VERSION 5.7 ;
  NOWIREEXTENSIONATPIN ON ;
  DIVIDERCHAR "/" ;
  BUSBITCHARS "[]" ;
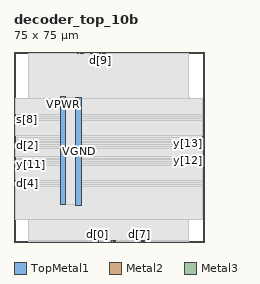
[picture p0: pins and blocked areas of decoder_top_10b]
MACRO decoder_top_10b
  CLASS BLOCK ;
  FOREIGN decoder_top_10b ;
  ORIGIN 0.000 0.000 ;
  SIZE 75.000 BY 75.000 ;
  PIN VGND
    DIRECTION INOUT ;
    USE GROUND ;
    PORT
      LAYER TopMetal1 ;
        RECT 24.460 14.490 26.660 56.920 ;
    END
  END VGND
  PIN VPWR
    DIRECTION INOUT ;
    USE POWER ;
    PORT
      LAYER TopMetal1 ;
        RECT 18.260 14.900 20.460 57.330 ;
    END
  END VPWR
  PIN d[0]
    DIRECTION INPUT ;
    USE SIGNAL ;
    ANTENNAGATEAREA 0.180700 ;
    PORT
      LAYER Metal2 ;
        RECT 32.920 0.000 33.320 0.400 ;
    END
  END d[0]
  PIN d[1]
    DIRECTION INPUT ;
    USE SIGNAL ;
    ANTENNAGATEAREA 0.180700 ;
    PORT
      LAYER Metal2 ;
        RECT 31.960 0.000 32.360 0.400 ;
    END
  END d[1]
  PIN d[2]
    DIRECTION INPUT ;
    USE SIGNAL ;
    ANTENNAGATEAREA 0.180700 ;
    PORT
      LAYER Metal3 ;
        RECT 0.000 38.020 0.400 38.420 ;
    END
  END d[2]
  PIN d[3]
    DIRECTION INPUT ;
    USE SIGNAL ;
    ANTENNAGATEAREA 0.180700 ;
    PORT
      LAYER Metal3 ;
        RECT 0.000 37.180 0.400 37.580 ;
    END
  END d[3]
  PIN d[4]
    DIRECTION INPUT ;
    USE SIGNAL ;
    ANTENNAGATEAREA 0.180700 ;
    PORT
      LAYER Metal3 ;
        RECT 0.000 22.900 0.400 23.300 ;
    END
  END d[4]
  PIN d[5]
    DIRECTION INPUT ;
    USE SIGNAL ;
    ANTENNAGATEAREA 0.180700 ;
    PORT
      LAYER Metal2 ;
        RECT 25.240 74.600 25.640 75.000 ;
    END
  END d[5]
  PIN d[6]
    DIRECTION INPUT ;
    USE SIGNAL ;
    ANTENNAGATEAREA 0.180700 ;
    PORT
      LAYER Metal2 ;
        RECT 30.040 74.600 30.440 75.000 ;
    END
  END d[6]
  PIN d[7]
    DIRECTION INPUT ;
    USE SIGNAL ;
    ANTENNAGATEAREA 0.180700 ;
    PORT
      LAYER Metal2 ;
        RECT 49.240 0.000 49.640 0.400 ;
    END
  END d[7]
  PIN d[8]
    DIRECTION INPUT ;
    USE SIGNAL ;
    ANTENNAGATEAREA 0.180700 ;
    PORT
      LAYER Metal3 ;
        RECT 0.000 48.940 0.400 49.340 ;
    END
  END d[8]
  PIN d[9]
    DIRECTION INPUT ;
    USE SIGNAL ;
    ANTENNAGATEAREA 0.180700 ;
    PORT
      LAYER Metal2 ;
        RECT 33.880 74.600 34.280 75.000 ;
    END
  END d[9]
  PIN s[4]
    DIRECTION OUTPUT ;
    USE SIGNAL ;
    ANTENNADIFFAREA 0.708600 ;
    PORT
      LAYER Metal3 ;
        RECT 0.000 22.060 0.400 22.460 ;
    END
  END s[4]
  PIN s[5]
    DIRECTION OUTPUT ;
    USE SIGNAL ;
    ANTENNADIFFAREA 0.708600 ;
    PORT
      LAYER Metal2 ;
        RECT 27.160 74.600 27.560 75.000 ;
    END
  END s[5]
  PIN s[6]
    DIRECTION OUTPUT ;
    USE SIGNAL ;
    ANTENNADIFFAREA 0.708600 ;
    PORT
      LAYER Metal2 ;
        RECT 31.960 74.600 32.360 75.000 ;
    END
  END s[6]
  PIN s[7]
    DIRECTION OUTPUT ;
    USE SIGNAL ;
    ANTENNADIFFAREA 0.708600 ;
    PORT
      LAYER Metal2 ;
        RECT 51.160 0.000 51.560 0.400 ;
    END
  END s[7]
  PIN s[8]
    DIRECTION OUTPUT ;
    USE SIGNAL ;
    ANTENNADIFFAREA 0.708600 ;
    PORT
      LAYER Metal3 ;
        RECT 0.000 48.100 0.400 48.500 ;
    END
  END s[8]
  PIN s[9]
    DIRECTION OUTPUT ;
    USE SIGNAL ;
    ANTENNADIFFAREA 0.708600 ;
    PORT
      LAYER Metal2 ;
        RECT 35.800 74.600 36.200 75.000 ;
    END
  END s[9]
  PIN sb[4]
    DIRECTION OUTPUT ;
    USE SIGNAL ;
    ANTENNADIFFAREA 0.708600 ;
    PORT
      LAYER Metal3 ;
        RECT 0.000 23.740 0.400 24.140 ;
    END
  END sb[4]
  PIN sb[5]
    DIRECTION OUTPUT ;
    USE SIGNAL ;
    ANTENNADIFFAREA 0.708600 ;
    PORT
      LAYER Metal2 ;
        RECT 26.200 74.600 26.600 75.000 ;
    END
  END sb[5]
  PIN sb[6]
    DIRECTION OUTPUT ;
    USE SIGNAL ;
    ANTENNADIFFAREA 0.708600 ;
    PORT
      LAYER Metal2 ;
        RECT 31.000 74.600 31.400 75.000 ;
    END
  END sb[6]
  PIN sb[7]
    DIRECTION OUTPUT ;
    USE SIGNAL ;
    ANTENNADIFFAREA 0.708600 ;
    PORT
      LAYER Metal2 ;
        RECT 50.200 0.000 50.600 0.400 ;
    END
  END sb[7]
  PIN sb[8]
    DIRECTION OUTPUT ;
    USE SIGNAL ;
    ANTENNADIFFAREA 0.708600 ;
    PORT
      LAYER Metal3 ;
        RECT 0.000 49.780 0.400 50.180 ;
    END
  END sb[8]
  PIN sb[9]
    DIRECTION OUTPUT ;
    USE SIGNAL ;
    ANTENNADIFFAREA 0.708600 ;
    PORT
      LAYER Metal2 ;
        RECT 34.840 74.600 35.240 75.000 ;
    END
  END sb[9]
  PIN y[0]
    DIRECTION OUTPUT ;
    USE SIGNAL ;
    ANTENNADIFFAREA 0.708600 ;
    PORT
      LAYER Metal2 ;
        RECT 39.640 0.000 40.040 0.400 ;
    END
  END y[0]
  PIN y[10]
    DIRECTION OUTPUT ;
    USE SIGNAL ;
    ANTENNADIFFAREA 0.708600 ;
    PORT
      LAYER Metal3 ;
        RECT 0.000 41.380 0.400 41.780 ;
    END
  END y[10]
  PIN y[11]
    DIRECTION OUTPUT ;
    USE SIGNAL ;
    ANTENNADIFFAREA 0.708600 ;
    PORT
      LAYER Metal3 ;
        RECT 0.000 30.460 0.400 30.860 ;
    END
  END y[11]
  PIN y[12]
    DIRECTION OUTPUT ;
    USE SIGNAL ;
    ANTENNADIFFAREA 0.708600 ;
    PORT
      LAYER Metal3 ;
        RECT 74.600 32.140 75.000 32.540 ;
    END
  END y[12]
  PIN y[13]
    DIRECTION OUTPUT ;
    USE SIGNAL ;
    ANTENNADIFFAREA 0.708600 ;
    PORT
      LAYER Metal3 ;
        RECT 74.600 38.860 75.000 39.260 ;
    END
  END y[13]
  PIN y[14]
    DIRECTION OUTPUT ;
    USE SIGNAL ;
    ANTENNADIFFAREA 0.708600 ;
    PORT
      LAYER Metal3 ;
        RECT 74.600 41.380 75.000 41.780 ;
    END
  END y[14]
  PIN y[15]
    DIRECTION OUTPUT ;
    USE SIGNAL ;
    ANTENNADIFFAREA 0.708600 ;
    PORT
      LAYER Metal3 ;
        RECT 0.000 32.980 0.400 33.380 ;
    END
  END y[15]
  PIN y[1]
    DIRECTION OUTPUT ;
    USE SIGNAL ;
    ANTENNADIFFAREA 0.708600 ;
    PORT
      LAYER Metal3 ;
        RECT 0.000 38.860 0.400 39.260 ;
    END
  END y[1]
  PIN y[2]
    DIRECTION OUTPUT ;
    USE SIGNAL ;
    ANTENNADIFFAREA 0.708600 ;
    PORT
      LAYER Metal3 ;
        RECT 0.000 40.540 0.400 40.940 ;
    END
  END y[2]
  PIN y[3]
    DIRECTION OUTPUT ;
    USE SIGNAL ;
    ANTENNADIFFAREA 0.708600 ;
    PORT
      LAYER Metal3 ;
        RECT 0.000 31.300 0.400 31.700 ;
    END
  END y[3]
  PIN y[4]
    DIRECTION OUTPUT ;
    USE SIGNAL ;
    ANTENNADIFFAREA 0.708600 ;
    PORT
      LAYER Metal3 ;
        RECT 74.600 32.980 75.000 33.380 ;
    END
  END y[4]
  PIN y[5]
    DIRECTION OUTPUT ;
    USE SIGNAL ;
    ANTENNADIFFAREA 0.708600 ;
    PORT
      LAYER Metal3 ;
        RECT 74.600 39.700 75.000 40.100 ;
    END
  END y[5]
  PIN y[6]
    DIRECTION OUTPUT ;
    USE SIGNAL ;
    ANTENNADIFFAREA 0.708600 ;
    PORT
      LAYER Metal3 ;
        RECT 74.600 40.540 75.000 40.940 ;
    END
  END y[6]
  PIN y[7]
    DIRECTION OUTPUT ;
    USE SIGNAL ;
    ANTENNADIFFAREA 0.708600 ;
    PORT
      LAYER Metal3 ;
        RECT 0.000 32.140 0.400 32.540 ;
    END
  END y[7]
  PIN y[8]
    DIRECTION OUTPUT ;
    USE SIGNAL ;
    ANTENNADIFFAREA 0.708600 ;
    PORT
      LAYER Metal2 ;
        RECT 38.680 0.000 39.080 0.400 ;
    END
  END y[8]
  PIN y[9]
    DIRECTION OUTPUT ;
    USE SIGNAL ;
    ANTENNADIFFAREA 0.708600 ;
    PORT
      LAYER Metal3 ;
        RECT 0.000 39.700 0.400 40.100 ;
    END
  END y[9]
  OBS
      LAYER GatPoly ;
        RECT 5.760 14.970 69.120 56.850 ;
      LAYER Metal1 ;
        RECT 5.760 14.900 69.120 56.920 ;
      LAYER Metal2 ;
        RECT 5.655 74.390 25.030 74.600 ;
        RECT 25.850 74.390 25.990 74.600 ;
        RECT 26.810 74.390 26.950 74.600 ;
        RECT 27.770 74.390 29.830 74.600 ;
        RECT 30.650 74.390 30.790 74.600 ;
        RECT 31.610 74.390 31.750 74.600 ;
        RECT 32.570 74.390 33.670 74.600 ;
        RECT 34.490 74.390 34.630 74.600 ;
        RECT 35.450 74.390 35.590 74.600 ;
        RECT 36.410 74.390 68.745 74.600 ;
        RECT 5.655 0.610 68.745 74.390 ;
        RECT 5.655 0.100 31.750 0.610 ;
        RECT 32.570 0.100 32.710 0.610 ;
        RECT 33.530 0.100 38.470 0.610 ;
        RECT 39.290 0.100 39.430 0.610 ;
        RECT 40.250 0.100 49.030 0.610 ;
        RECT 49.850 0.100 49.990 0.610 ;
        RECT 50.810 0.100 50.950 0.610 ;
        RECT 51.770 0.100 68.745 0.610 ;
      LAYER Metal3 ;
        RECT 0.400 50.390 74.600 56.800 ;
        RECT 0.610 49.570 74.600 50.390 ;
        RECT 0.400 49.550 74.600 49.570 ;
        RECT 0.610 48.730 74.600 49.550 ;
        RECT 0.400 48.710 74.600 48.730 ;
        RECT 0.610 47.890 74.600 48.710 ;
        RECT 0.400 41.990 74.600 47.890 ;
        RECT 0.610 41.170 74.390 41.990 ;
        RECT 0.400 41.150 74.600 41.170 ;
        RECT 0.610 40.330 74.390 41.150 ;
        RECT 0.400 40.310 74.600 40.330 ;
        RECT 0.610 39.490 74.390 40.310 ;
        RECT 0.400 39.470 74.600 39.490 ;
        RECT 0.610 38.650 74.390 39.470 ;
        RECT 0.400 38.630 74.600 38.650 ;
        RECT 0.610 37.810 74.600 38.630 ;
        RECT 0.400 37.790 74.600 37.810 ;
        RECT 0.610 36.970 74.600 37.790 ;
        RECT 0.400 33.590 74.600 36.970 ;
        RECT 0.610 32.770 74.390 33.590 ;
        RECT 0.400 32.750 74.600 32.770 ;
        RECT 0.610 31.930 74.390 32.750 ;
        RECT 0.400 31.910 74.600 31.930 ;
        RECT 0.610 31.090 74.600 31.910 ;
        RECT 0.400 31.070 74.600 31.090 ;
        RECT 0.610 30.250 74.600 31.070 ;
        RECT 0.400 24.350 74.600 30.250 ;
        RECT 0.610 23.530 74.600 24.350 ;
        RECT 0.400 23.510 74.600 23.530 ;
        RECT 0.610 22.690 74.600 23.510 ;
        RECT 0.400 22.670 74.600 22.690 ;
        RECT 0.610 21.850 74.600 22.670 ;
        RECT 0.400 8.720 74.600 21.850 ;
      LAYER Metal4 ;
        RECT 18.440 14.975 26.480 56.845 ;
      LAYER Metal5 ;
        RECT 18.395 14.810 26.525 57.010 ;
  END
END decoder_top_10b
END LIBRARY

